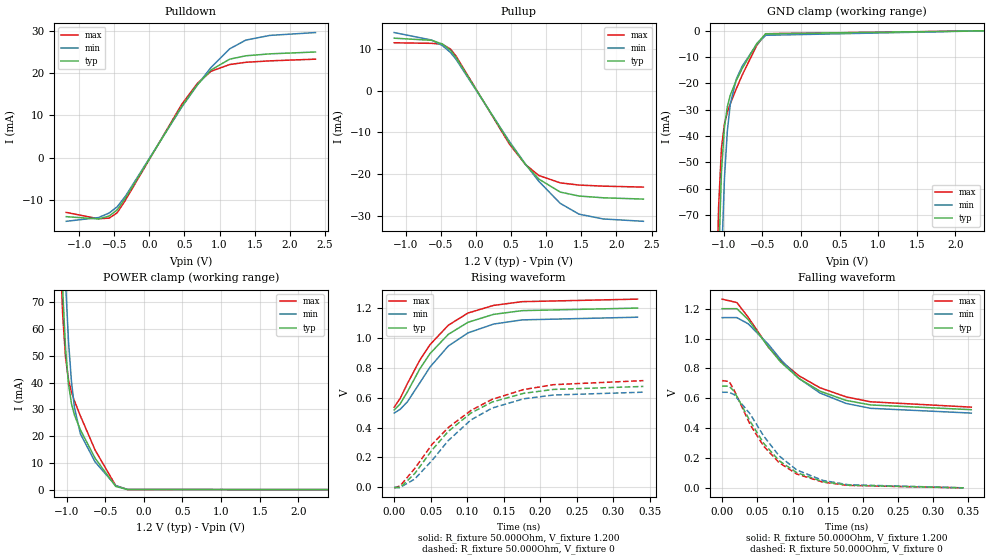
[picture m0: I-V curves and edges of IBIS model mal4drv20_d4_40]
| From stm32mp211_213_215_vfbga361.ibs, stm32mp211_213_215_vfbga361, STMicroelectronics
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[Model] mal4drv20_d4_40
Model_type   I/O
Polarity   Non-Inverting
Enable   Active-High
C_comp   1.838pF   1.835pF   1.848pF
C_comp_pullup   938.881fF   931.604fF   947.115fF
C_comp_pulldown 782.410fF   779.859fF   796.520fF
Vinh = 668.000mV
Vinl = 532.000mV
Vmeas = 600.000mV
Vref = 600.000mV
Rref = 50Ohms
Cref = 0pF
[Model Spec]
Vinh   668.000mV   638.000mV   698.000mV
Vinl   532.000mV   502.000mV   562.000mV
Vmeas   600.000mV   570.000mV   630.000mV
Vref   600.000mV   570.000mV   630.000mV
D_overshoot_ampl_h 0.24 NA   NA
D_overshoot_ampl_l 0.24 NA   NA
D_overshoot_area_l 300.000m NA   NA
D_overshoot_area_h 300.000m NA   NA
[Receiver Thresholds]
Vth = 600.000mV
Vth_min = 570.000mV
Vth_max = 630.000mV
Vinh_ac = 68.000mV
Vinh_dc = 68.000mV
Vinl_ac = -68.000mV
Vinl_dc = -68.000mV
Tslew_ac = 5.000ns
Threshold_sensitivity = 0.5
Reference_supply Pullup_ref
[Temperature Range]   25.000   125.000   -40.000
[Voltage Range]   1.200V   1.140V   1.260V
[GND Clamp Reference]   0.00V   0.00V   0.00V
[C Comp Corner]
| variable   typ   min   max
C_comp 1.848pF   1.838pF   1.835pF
C_comp_pullup 938.881fF   947.115fF   931.604fF
C_comp_pulldown 779.859fF   796.520fF   782.410fF
[Pulldown Reference]   0.00V   0.00V   0.00V
[POWER Clamp Reference]   1.200V   1.140V   1.260V
[Pullup Reference]   1.200V   1.140V   1.260V
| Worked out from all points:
|   slope of the pulldown table from 0 to 0.18 V, typ, clamps not added: 36.7 ohm
|   slope of the pullup table from 0 to 0.18 V, typ, clamps not added: 37 ohm
|   GND clamp passes 1 mA (typ) near -0.45 V on its own axis
|   POWER clamp passes 1 mA (typ) near -0.35 V on its own axis
|   rising waveform, R_fixture 50.000Ohm, V_fixture 1.200: 20-80 % time 65.2ps typ, 66.6ps min, 65.5ps max; typ from 0.518 V to 1.2 V
|   rising waveform, R_fixture 50.000Ohm, V_fixture 0: 20-80 % time 85.5ps typ, 82.2ps min, 96ps max; typ from -0.002 V to 0.675 V
|   falling waveform, R_fixture 50.000Ohm, V_fixture 1.200: 20-80 % time 86.6ps typ, 85.3ps min, 92ps max; typ from 1.2 V to 0.524 V
|   falling waveform, R_fixture 50.000Ohm, V_fixture 0: 20-80 % time 63.9ps typ, 65.6ps min, 63.3ps max; typ from 0.681 V to 0 V
[GND Clamp]
-1.184V   -365mA     -429.3mA   -336.5mA
-1.107V   -152.4mA   -215.7mA   -121.1mA
-1.069V   -88.87mA   -140.5mA   -67.62mA
-1.031V   -53.54mA   -88.39mA   -44.48mA
-992.7mV  -36.7mA    -56.18mA   -35.42mA
-954.6mV  -28.78mA   -37.93mA   -30.92mA
-916.4mV  -24.43mA   -27.89mA   -27.7mA
-840mV    -18.89mA   -18.42mA   -22.12mA
-763.6mV  -14.38mA   -13.51mA   -16.88mA
-572.7mV  -4.818mA   -5.067mA   -5.477mA
-458.2mV  -1.146mA   -1.695mA   -1.103mA
2.367V    25.44nA    625nA      8.401nA
[Power Clamp]
-1.167V   197.6mA    234.2mA    183.1mA
-1.091V   108mA      144mA      94.42mA
-1.053V   75.21mA    107.2mA    65.93mA
-1.015V   52.65mA    77.42mA    49.33mA
-976.4mV  39.37mA    55.31mA    41.02mA
-938.2mV  32.15mA    40.29mA    36.48mA
-900mV    27.91mA    30.75mA    33.22mA
-823.6mV  22.42mA    20.91mA    27.62mA
-632.7mV  11.76mA    10.36mA    14.83mA
-365.4mV  1.178mA    1.496mA    1.508mA
-212.7mV  14.35uA    76.22uA    9.056uA
2.384V    -16.74nA   -562.7nA   -5.86nA
[Pulldown]
-1.184V   -14mA      -15.1mA    -13mA
-725.5mV  -14.55mA   -14.22mA   -14.51mA
-572.7mV  -13.85mA   -13.14mA   -14.34mA
-458.2mV  -12.39mA   -11.66mA   -13.08mA
-343.6mV  -9.649mA   -9.219mA   -10.16mA
458.2mV   12.06mA    11.85mA    12.52mA
687.3mV   17.29mA    17.27mA    17.63mA
878.2mV   20.74mA    21.33mA    20.43mA
1.145V    23.3mA     25.75mA    22.03mA
1.375V    24.1mA     27.82mA    22.56mA
1.718V    24.56mA    28.93mA    22.9mA
2.367V    25mA       29.6mA     23.3mA
[Pullup]
-1.167V   12.5mA     13.84mA    11.4mA
-632.7mV  11.99mA    12.05mA    11.27mA
-480mV    11.11mA    10.73mA    11.03mA
-365.4mV  9.622mA    9.099mA    9.915mA
-289.1mV  7.956mA    7.545mA    8.303mA
474.6mV   -12.4mA    -12.14mA   -12.77mA
703.6mV   -17.64mA   -17.55mA   -17.65mA
894.5mV   -21.13mA   -21.67mA   -20.27mA
1.2V      -24.23mA   -26.93mA   -22.03mA
1.467V    -25.17mA   -29.5mA    -22.55mA
1.811V    -25.59mA   -30.64mA   -22.81mA
2.384V    -25.9mA    -31.2mA    -23.04mA
[Ramp]
R_load=50.000Ohm
dV/dt_r   407.010mV/77.500ps  384.238mV/76.000ps  432.030mV/82.500ps
dV/dt_f   407.010mV/76.500ps  384.239mV/77.000ps  432.030mV/79.500ps
[Rising waveform]
R_fixture=50.000Ohm
V_fixture=1.200
V_fixture_min=1.140
V_fixture_max=1.260
0s        518mV      497.4mV    537mV
8ps       557.4mV    521.6mV    593.8mV
18ps      638.7mV    572.2mV    693.8mV
35ps      792.5mV    699mV      851.1mV
49ps      895.4mV    804.9mV    955.1mV
74ps      1.024V     945.9mV    1.085V
101ps     1.105V     1.034V     1.167V
136ps     1.158V     1.093V     1.218V
175ps     1.183V     1.121V     1.243V
333ps     1.2V       1.139V     1.26V
[Rising waveform]
R_fixture=50.000Ohm
V_fixture=0
0s        -2.468mV   -405.1uV   -3.651mV
8ps       -2.468mV   -405.1uV   9.098mV
28ps      91.4mV     54.71mV    125.4mV
52ps      250.9mV    181.2mV    288.7mV
74ps      374.5mV    313.1mV    400.1mV
105ps     497.4mV    451.2mV    514.7mV
134ps     570.9mV    530.6mV    589mV
177ps     629.2mV    592.5mV    654.4mV
218ps     655.4mV    618mV      687.2mV
341ps     675.4mV    637mV      714.4mV
[Falling waveform]
R_fixture=50.000Ohm
V_fixture=1.200
V_fixture_min=1.140
V_fixture_max=1.260
0s        1.2V       1.14V      1.264V
21ps      1.2V       1.14V      1.241V
37ps      1.127V     1.099V     1.143V
66ps      942.3mV    959.7mV    941.3mV
83ps      843.7mV    861.1mV    851.8mV
109ps     733.1mV    733.7mV    751.3mV
139ps     647.9mV    635.6mV    670.6mV
176ps     586.1mV    565.9mV    609.9mV
211ps     555.5mV    532.9mV    576.5mV
354ps     523.8mV    501.1mV    540.9mV
[Falling waveform]
R_fixture=50.000Ohm
V_fixture=0
0s        681.1mV    640.4mV    718.6mV
10ps      681.1mV    640.4mV    712.7mV
17ps      646.9mV    624.7mV    654.7mV
40ps      444.8mV    494mV      422.2mV
59ps      299mV      347.4mV    279.8mV
81ps      182.1mV    214.6mV    169.1mV
106ps     102.5mV    120.2mV    93.04mV
143ps     42.08mV    50.32mV    38.92mV
179ps     18.24mV    21.49mV    16.69mV
343ps     427.2uV    610.2uV    392.4uV
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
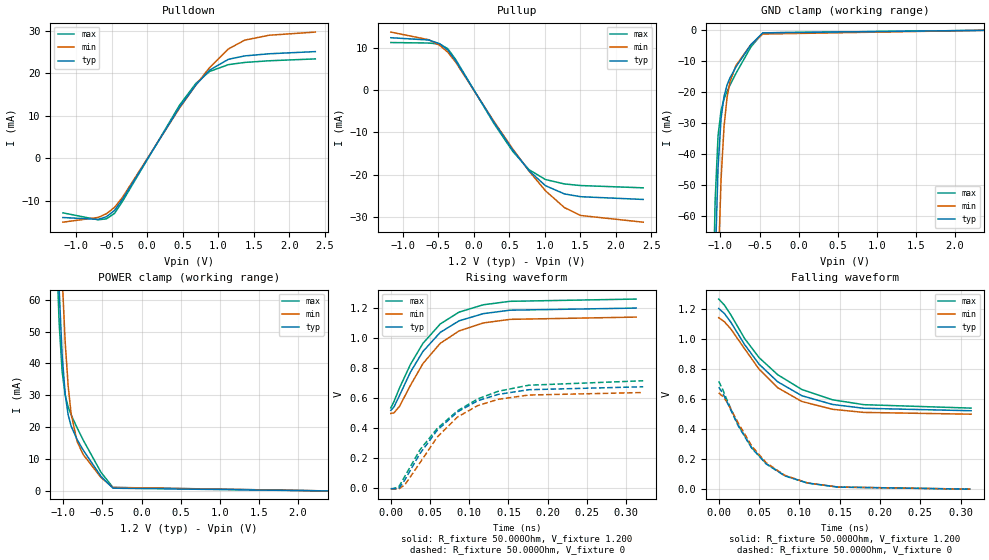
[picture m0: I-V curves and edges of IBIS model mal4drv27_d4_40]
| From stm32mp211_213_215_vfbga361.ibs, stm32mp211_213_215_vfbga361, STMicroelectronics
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[Model] mal4drv27_d4_40
Model_type   I/O
Polarity   Non-Inverting
Enable   Active-High
C_comp   1.656pF   1.652pF   1.661pF
C_comp_pullup   829.373fF   822.555fF   836.725fF
C_comp_pulldown 737.416fF   735.607fF   748.448fF
Vinh = 924.000mV
Vinl = 809.000mV
Vmeas = 867.000mV
Vref = 1.200V
Rref = 50Ohms
Cref = 0pF
[Model Spec]
Vinh   924.000mV   881.000mV   968.000mV
Vinl   809.000mV   766.000mV   853.000mV
Vmeas   867.000mV   823.000mV   910.000mV
Vref   1.200V   1.140V   1.260V
D_overshoot_ampl_h 0.24 NA   NA
D_overshoot_ampl_l 0.24 NA   NA
D_overshoot_area_l 300.000m NA   NA
D_overshoot_area_h 300.000m NA   NA
[Receiver Thresholds]
Vth = 867.000mV
Vth_min = 823.000mV
Vth_max = 910.000mV
Vinh_ac = 68.000mV
Vinh_dc = 68.000mV
Vinl_ac = -68.000mV
Vinl_dc = -68.000mV
Tslew_ac = 5.000ns
Threshold_sensitivity = 0.5
Reference_supply Pullup_ref
[Temperature Range]   25.000   125.000   -40.000
[Voltage Range]   1.200V   1.140V   1.260V
[GND Clamp Reference]   0.00V   0.00V   0.00V
[C Comp Corner]
| variable   typ   min   max
C_comp 1.661pF   1.656pF   1.652pF
C_comp_pullup 829.373fF   836.725fF   822.555fF
C_comp_pulldown 735.607fF   748.448fF   737.416fF
[Pulldown Reference]   0.00V   0.00V   0.00V
[POWER Clamp Reference]   1.200V   1.140V   1.260V
[Pullup Reference]   1.200V   1.140V   1.260V
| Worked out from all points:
|   slope of the pulldown table from 0 to 0.18 V, typ, clamps not added: 36.8 ohm
|   slope of the pullup table from 0 to 0.18 V, typ, clamps not added: 37.1 ohm
|   GND clamp passes 1 mA (typ) near -0.47 V on its own axis
|   POWER clamp passes 1 mA (typ) near -0.37 V on its own axis
|   rising waveform, R_fixture 50.000Ohm, V_fixture 1.200: 20-80 % time 55.4ps typ, 55.1ps min, 56ps max; typ from 0.52 V to 1.2 V
|   rising waveform, R_fixture 50.000Ohm, V_fixture 0: 20-80 % time 68ps typ, 63.2ps min, 78.3ps max; typ from -0.001 V to 0.676 V
|   falling waveform, R_fixture 50.000Ohm, V_fixture 1.200: 20-80 % time 68.9ps typ, 63.8ps min, 76.2ps max; typ from 1.2 V to 0.522 V
|   falling waveform, R_fixture 50.000Ohm, V_fixture 0: 20-80 % time 53.1ps typ, 52.9ps min, 53.3ps max; typ from 0.68 V to 0 V
[GND Clamp]
-1.184V   -313.6mA   -372.3mA   -285.9mA
-1.107V   -133mA     -190.9mA   -103.4mA
-1.069V   -76.66mA   -125mA     -55.43mA
-1.031V   -44.19mA   -77.99mA   -34.02mA
-992.7mV  -28.51mA   -48.19mA   -25.88mA
-954.6mV  -21.35mA   -31.1mA    -22.21mA
-916.4mV  -17.7mA    -21.78mA   -19.79mA
-878.2mV  -15.35mA   -16.61mA   -17.73mA
-801.8mV  -11.82mA   -11.34mA   -13.9mA
-610.9mV  -4.628mA   -4.618mA   -5.371mA
-458.2mV  -822.8uA   -1.198mA   -809uA
2.367V    18.95nA    454.6nA    6.243nA
[Power Clamp]
-1.167V   171.5mA    206.4mA    156.1mA
-1.091V   92.44mA    126.6mA    77.99mA
-1.053V   63.02mA    93.75mA    52.4mA
-1.015V   42.49mA    66.9mA     37.37mA
-976.4mV  30.34mA    46.72mA    30.02mA
-938.2mV  23.88mA    32.9mA     26.3mA
-900mV    20.31mA    24.15mA    23.84mA
-823.6mV  16.11mA    15.49mA    19.79mA
-747.3mV  12.87mA    11.46mA    16.02mA
-518.2mV  4.545mA    4.187mA    5.836mA
-365.4mV  856.5uA    1.078mA    1.107mA
2.384V    -12.74nA   -415.5nA   -4.625nA
[Pulldown]
-1.184V   -14mA      -15.1mA    -12.9mA
-687.3mV  -14.43mA   -13.98mA   -14.54mA
-572.7mV  -13.82mA   -13.11mA   -14.31mA
-458.2mV  -12.36mA   -11.62mA   -13.04mA
-343.6mV  -9.628mA   -9.199mA   -10.14mA
458.2mV   12.04mA    11.83mA    12.5mA
687.3mV   17.26mA    17.24mA    17.61mA
878.2mV   20.72mA    21.3mA     20.41mA
1.145V    23.29mA    25.73mA    22.03mA
1.375V    24.09mA    27.81mA    22.55mA
1.718V    24.59mA    28.96mA    22.94mA
2.367V    25.1mA     29.7mA     23.38mA
[Pullup]
-1.167V   12.5mA     13.84mA    11.36mA
-632.7mV  11.96mA    12.02mA    11.24mA
-480mV    11.09mA    10.7mA     11mA
-365.4mV  9.604mA    9.074mA    9.89mA
-250.9mV  6.931mA    6.616mA    7.242mA
283.6mV   -7.569mA   -7.358mA   -7.855mA
550.9mV   -14.2mA    -13.96mA   -14.54mA
780mV     -19.13mA   -19.21mA   -18.86mA
1.009V    -22.63mA   -23.84mA   -21.17mA
1.276V    -24.59mA   -27.84mA   -22.22mA
1.505V    -25.25mA   -29.71mA   -22.6mA
2.384V    -25.9mA    -31.3mA    -23.14mA
[Ramp]
R_load=50.000Ohm
dV/dt_r   406.620mV/62.500ps  383.909mV/60.000ps  431.640mV/68.000ps
dV/dt_f   406.620mV/62.000ps  383.909mV/59.500ps  431.640mV/66.500ps
[Rising waveform]
R_fixture=50.000Ohm
V_fixture=1.200
V_fixture_min=1.140
V_fixture_max=1.260
0s        519.8mV    498.9mV    535.7mV
4ps       541.8mV    503mV      577.8mV
11ps      617.1mV    545.4mV    667.7mV
25ps      773.8mV    685.4mV    824.7mV
41ps      911.6mV    830.9mV    965.5mV
63ps      1.038V     965.1mV    1.094V
87ps      1.115V     1.048V     1.173V
118ps     1.163V     1.101V     1.222V
152ps     1.186V     1.125V     1.245V
313ps     1.2V       1.14V      1.26V
[Rising waveform]
R_fixture=50.000Ohm
V_fixture=0
0s        -1.465mV   -3.842mV   -4.831mV
10ps      -1.465mV   -3.842mV   9.596mV
18ps      57.75mV    24.77mV    81.66mV
37ps      230.4mV    169.1mV    255.6mV
59ps      385.9mV    340.1mV    397.9mV
85ps      509.1mV    475.1mV    516.3mV
111ps     583.7mV    551.3mV    595.9mV
137ps     625.9mV    593.1mV    646.4mV
176ps     656.8mV    621.5mV    686.8mV
322ps     676.5mV    638.1mV    716.4mV
[Falling waveform]
R_fixture=50.000Ohm
V_fixture=1.200
V_fixture_min=1.140
V_fixture_max=1.260
0s        1.203V     1.142V     1.266V
7ps       1.17V      1.115V     1.226V
15ps      1.112V     1.067V     1.161V
32ps      963.7mV    935.7mV    1.004V
50ps      832.5mV    799.4mV    876.5mV
73ps      715.6mV    676mV      762.7mV
103ps     622.5mV    584.2mV    663.9mV
141ps     564.3mV    532.1mV    595.3mV
180ps     538.7mV    511.2mV    562.7mV
313ps     522.4mV    499.3mV    539.8mV
[Falling waveform]
R_fixture=50.000Ohm
V_fixture=0
0s        679.5mV    641.4mV    718.5mV
5ps       639.5mV    617.5mV    663.1mV
10ps      584.4mV    582.5mV    597.1mV
24ps      423.1mV    442.7mV    429.1mV
41ps      272.3mV    287mV      275.9mV
59ps      167.3mV    175.2mV    169.7mV
82ps      88.41mV    92.3mV     89.81mV
110ps     40.7mV     41.69mV    41.1mV
148ps     13.69mV    14.15mV    14.33mV
312ps     109.5uV    137.7uV    112.1uV
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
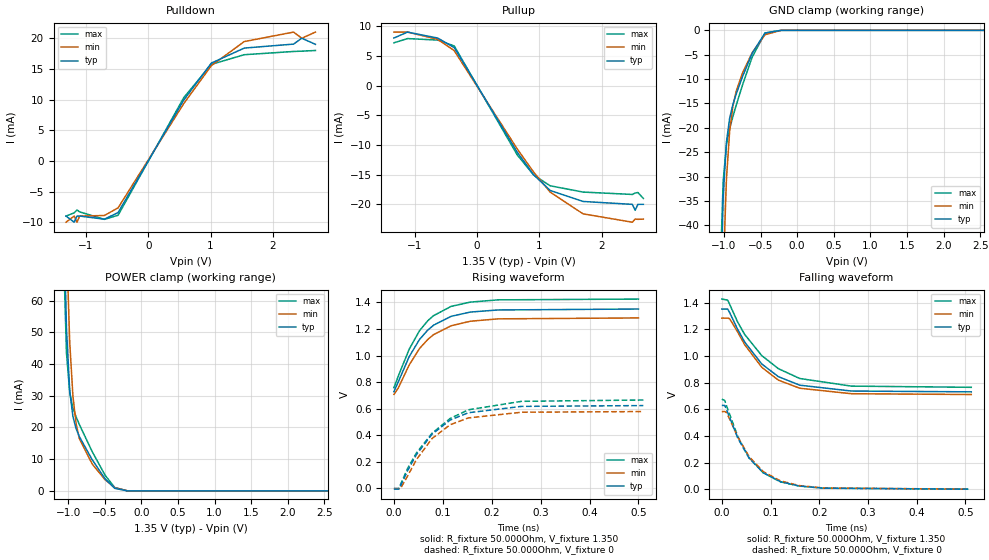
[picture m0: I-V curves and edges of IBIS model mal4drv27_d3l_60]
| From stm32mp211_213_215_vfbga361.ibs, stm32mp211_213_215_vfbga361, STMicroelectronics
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[Model] mal4drv27_d3l_60
Model_type   I/O
Polarity   Non-Inverting
Enable   Active-High
C_comp   1.684pF   1.663pF   1.711pF
C_comp_pullup   812.334fF   800.254fF   826.800fF
C_comp_pulldown   769.309fF   756.297fF   787.425fF
Vinh = 805.000mV
Vinl = 545.000mV
Vmeas = 675.000mV
Vref = 675.000mV
Rref = 50Ohms
Cref = 0pF
[Model Spec]
Vinh   805.000mV   772.000mV   855.000mV
Vinl   545.000mV   512.000mV   595.000mV
Vmeas   675.000mV   642.000mV   725.000mV
Vref   675.000mV   642.000mV   725.000mV
D_overshoot_ampl_h 0.4 NA   NA
D_overshoot_ampl_l 0.4 NA   NA
D_overshoot_area_l 110.000m NA   NA
D_overshoot_area_h 110.000m NA   NA
[Temperature Range]   25.000   125.000   -40.000
[Voltage Range]   1.350V   1.283V   1.425V
[GND Clamp Reference]   0.00V   0.00V   0.00V
[C Comp Corner]
| variable   typ   min   max
C_comp   1.684pF   1.663pF   1.711pF
C_comp_pullup   812.334fF   800.254fF   826.800fF
C_comp_pulldown   769.309fF   756.297fF   787.425fF
[Pulldown Reference]   0.00V   0.00V   0.00V
[POWER Clamp Reference]   1.350V   1.283V   1.425V
[Pullup Reference]   1.350V   1.283V   1.425V
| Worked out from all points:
|   slope of the pulldown table from 0 to 0.203 V, typ, clamps not added: 55.4 ohm
|   slope of the pullup table from 0 to 0.203 V, typ, clamps not added: 55.2 ohm
|   GND clamp passes 1 mA (typ) near -0.47 V on its own axis
|   POWER clamp passes 1 mA (typ) near -0.37 V on its own axis
|   rising waveform, R_fixture 50.000Ohm, V_fixture 1.350: 20-80 % time 65.7ps typ, 68.1ps min, 64.5ps max; typ from 0.728 V to 1.35 V
|   rising waveform, R_fixture 50.000Ohm, V_fixture 0: 20-80 % time 81.2ps typ, 76.1ps min, 92.3ps max; typ from -0.006 V to 0.623 V
|   falling waveform, R_fixture 50.000Ohm, V_fixture 1.350: 20-80 % time 82.6ps typ, 79.1ps min, 92.4ps max; typ from 1.35 V to 0.73 V
|   falling waveform, R_fixture 50.000Ohm, V_fixture 0: 20-80 % time 64.5ps typ, 67.3ps min, 63.4ps max; typ from 0.628 V to 0 V
[GND Clamp]
-1.318V   -672mA     -638mA     -661.1mA
-1.054V   -60.41mA   -84.99mA   -50.75mA
-1.011V   -34.02mA   -49.92mA   -30.84mA
-966.7mV  -22.91mA   -30.54mA   -23.58mA
-922.7mV  -18.04mA   -20.68mA   -20.16mA
-878.8mV  -15.25mA   -15.56mA   -17.69mA
-834.8mV  -13.14mA   -12.55mA   -15.44mA
-747mV    -9.486mA   -8.743mA   -11.21mA
-615.2mV  -4.709mA   -4.591mA   -5.504mA
-439.4mV  -562.2uA   -889.5uA   -546.1uA
-219.7mV  -954.1nA   -9.356uA   -215nA
2.68V     18.98nA    945nA      23.53nA
[Power Clamp]
-1.33V    889mA      842.2mA    872.8mA
-1.067V   94.44mA    130.9mA    77.96mA
-1.023V   51.04mA    78.45mA    43.53mA
-978.8mV  31.54mA    46.94mA    31.01mA
-934.8mV  23.45mA    29.85mA    26.15mA
-890.9mV  19.58mA    21.13mA    23.3mA
-847mV    17.11mA    16.47mA    20.93mA
-671.2mV  9.815mA    8.474mA    12.37mA
-495.5mV  3.823mA    3.529mA    4.955mA
-363.6mV  819.5uA    1.024mA    1.072mA
-187.9mV  4.227uA    28.6uA     2.566uA
2.668V    -29.12nA   -796.8nA   -15.73nA
[Pulldown]
-1.318V   -9mA       -10mA      -9mA
-1.186V   -10mA      -9mA       -8.475mA
-1.142V   -9mA       -10mA      -8mA
-1.099V   -9mA       -9mA       -8.319mA
-703mV    -9.511mA   -8.91mA    -9.54mA
-483.3mV  -8.432mA   -7.665mA   -8.87mA
571.2mV   9.942mA    9.369mA    10.34mA
1.011V    15.94mA    15.52mA    15.73mA
1.538V    18.39mA    19.45mA    17.31mA
2.329V    19.04mA    21mA       17.84mA
2.461V    20mA       20mA       17.89mA
2.68V     19mA       21mA       18mA
[Pullup]
-1.33V    8mA        9mA        7.193mA
-1.111V   9mA        9mA        7.908mA
-627.3mV  7.993mA    7.774mA    7.654mA
-363.6mV  6.396mA    5.879mA    6.67mA
647mV     -11.23mA   -10.68mA   -11.68mA
910.6mV   -15.03mA   -14.58mA   -15.07mA
1.174V    -17.66mA   -17.93mA   -16.87mA
1.702V    -19.51mA   -21.6mA    -17.93mA
2.492V    -20mA      -23mA      -18.33mA
2.536V    -21mA      -22.47mA   -18.09mA
2.58V     -20mA      -22.52mA   -18mA
2.668V    -20mA      -22.48mA   -19mA
[Ramp]
R_load=50.000Ohm
dV/dt_r   372.900mV/74.500ps  345.298mV/73.000ps  397.800mV/79.500ps
dV/dt_f   372.900mV/75.000ps  345.299mV/74.500ps  397.800mV/78.500ps
[Rising waveform]
R_fixture=50.000Ohm
V_fixture=1.350
V_fixture_min=1.283
V_fixture_max=1.425
0s        728mV      707mV      758mV
9ps       802mV      756mV      845mV
31ps      990mV      927mV      1.046V
52ps      1.119V     1.051V     1.185V
69ps      1.191V     1.12V      1.261V
81ps      1.228V     1.157V     1.3V
117ps     1.295V     1.224V     1.37V
156ps     1.327V     1.258V     1.402V
213ps     1.343V     1.276V     1.419V
500ps     1.35V      1.283V     1.425V
[Rising waveform]
R_fixture=50.000Ohm
V_fixture=0
0s        -6.304mV   -2.587mV   -973.7uV
10ps      -6.304mV   -2.587mV   -973.7uV
14ps      21.86mV    1.806mV    33.3mV
28ps      133mV      92.81mV    150mV
46ps      254mV      216mV      266mV
78ps      408mV      375mV      415mV
115ps     514mV      479mV      526mV
152ps     569mV      530mV      591mV
261ps     617mV      573mV      655mV
510ps     623mV      578mV      665mV
[Falling waveform]
R_fixture=50.000Ohm
V_fixture=1.350
V_fixture_min=1.283
V_fixture_max=1.425
0s        1.351V     1.283V     1.426V
12ps      1.351V     1.283V     1.418V
16ps      1.325V     1.279V     1.387V
32ps      1.202V     1.182V     1.257V
47ps      1.103V     1.083V     1.16V
82ps      939mV      914mV      1.002V
116ps     844mV      818mV      904mV
160ps     780mV      757mV      830mV
266ps     736mV      716mV      773mV
512ps     730mV      710mV      764mV
[Falling waveform]
R_fixture=50.000Ohm
V_fixture=0
0s        628mV      582mV      675mV
6ps       628mV      582mV      665mV
10ps      593mV      573mV      622mV
33ps      381mV      389mV      393mV
56ps      232mV      244mV      237mV
85ps      123mV      132mV      123mV
120ps     56.44mV    62.59mV    55.25mV
159ps     23.51mV    26.9mV     22.77mV
209ps     7.488mV    9.093mV    7.225mV
506ps     6.607uV    14.31uV    1.806uV
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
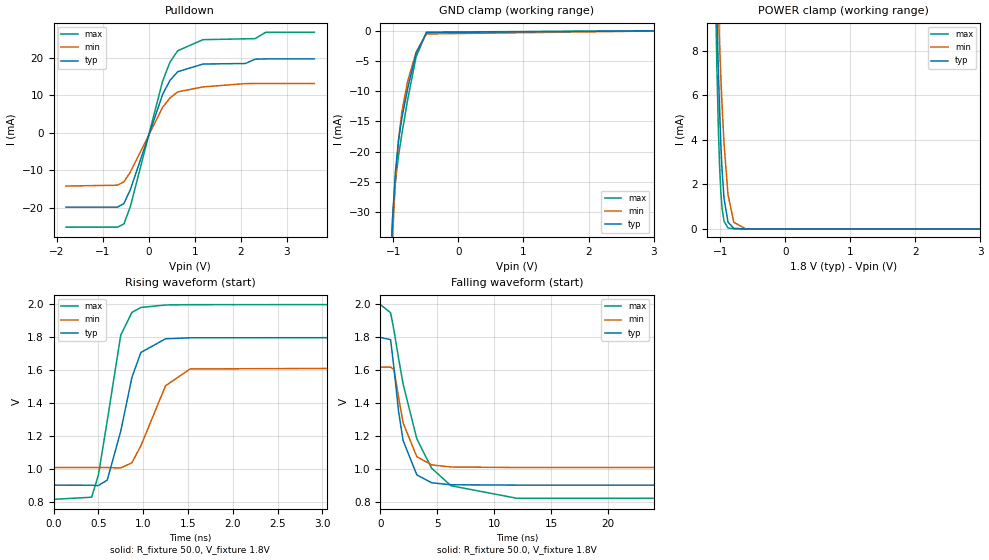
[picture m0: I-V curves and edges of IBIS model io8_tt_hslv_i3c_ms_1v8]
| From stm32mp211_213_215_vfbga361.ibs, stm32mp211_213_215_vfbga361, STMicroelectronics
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[Model]   io8_tt_hslv_i3c_ms_1v8
Model_type I/O_open_drain
Polarity   Non-Inverting
Enable   Active-Low
| CAP_THRESHOLD on pad IOTT is "UDTCAPC" :
| Rising=30.0% of vddiov33m   Falling=70.0% of vddiov33m
| C_comp min and max val. don't necessarily correlate with the min and max pvt
| but are the smallest and greatest pad capacitance found.
| var   typ   min   max
C_comp   1.23120pF  1.11692pF  1.38090pF
|C_comp_pulldown   1.23120pF  1.11692pF  1.38090pF
Vinl = 810.0mV
Vinh = 1.0V
Vmeas = 900.0mV   | Reference voltage for timing measurements
Cref  = 50.0pF   | Timing specification test load capacitance value
Rref  = 1.0MOhm   | Timing specification test load resistance value
Vref  = 990.0mV   | Timing specification test load voltage
[Model Spec]
| TIME_THRESHOLD on pin ZIV08M is "CMOS" :
| Rising=50.0% of vddv08m   Falling=50.0% of vddv08m
Vinl 675.70000mV 623.70000mV 735.70000mV
Vinh 1.12730V 1.01130V 1.24930V
| variable   typ   min   max
[Temperature Range] 25.0 125.0 -40.0
| variable   typ   min   max
[Voltage Range] 1.8V 1.62V 2.0V
| variable   typ   min   max
[POWER Clamp Reference] 1.8V 1.62V 2.0V
| variable   typ   min   max
[GND Clamp Reference] 0V 0V 0V
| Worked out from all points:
|   slope of the pulldown table from 0 to 0.27 V, typ, clamps not added: 28.9 ohm
|   GND clamp passes 1 mA (typ) near -0.55 V on its own axis
|   POWER clamp passes 1 mA (typ) near -0.93 V on its own axis
|   rising waveform, R_fixture 50.0, V_fixture 1.8V: 20-80 % time 220ps typ, 275ps min, 197ps max; typ from 0.904 V to 1.8 V
|   falling waveform, R_fixture 50.0, V_fixture 1.8V: 20-80 % time 1.14ns typ, 1.22ns min, 2.67ns max; typ from 1.8 V to 0.904 V
[POWER Clamp]
-1.8V     152.1mA    105.6mA    221.1mA
-1.07V    12.07mA    13.61mA    10.38mA
-1.05V    9.569mA    11.75mA    7.248mA
-1.03V    7.339mA    9.993mA    4.743mA
-1.01V    5.42mA     8.357mA    2.898mA
-990mV    3.841mA    6.859mA    1.662mA
-970mV    2.609mA    5.513mA    906.4uA
-940mV    1.358mA    3.806mA    344.1uA
-880mV    308.2uA    1.548mA    45.5uA
-790mV    28.46uA    298.8uA    2.106uA
-610mV    211.8nA    7.522uA    9.52nA
3.6V      0A         0A         0A
[GND Clamp]
-1.8V     -1.222A    -1.193A    -1.238A
-1.05V    -42.33mA   -45.55mA   -41.2mA
-1.04V    -38.89mA   -42.1mA    -37.88mA
-1.03V    -35.83mA   -38.98mA   -35.06mA
-1.01V    -30.7mA    -33.54mA   -30.61mA
-970mV    -23.47mA   -25.17mA   -24.97mA
-920mV    -18.06mA   -18.06mA   -20.63mA
-870mV    -14.51mA   -13.44mA   -17.13mA
-780mV    -9.532mA   -8.354mA   -11.38mA
-650mV    -3.743mA   -3.581mA   -4.327mA
-490mV    -324.1uA   -556uA     -259.6uA
3.6V      66.06nA    2.767uA    18.5nA
| variable   typ   min   max
[Pullup Reference] 1.8V 1.62V 2.0V
| variable   typ   min   max
[Pulldown Reference] 0V 0V 0V
[Pulldown]
-1.8V     -19.85mA   -14.22mA   -25.2mA
-680mV    -19.85mA   -13.99mA   -25.2mA
-540mV    -18.89mA   -13.07mA   -24.34mA
-400mV    -15.16mA   -10.48mA   -19.7mA
300mV     10.22mA    6.776mA    13.77mA
460mV     14.01mA    9.309mA    18.88mA
630mV     16.33mA    10.94mA    21.94mA
1.18V     18.38mA    12.27mA    24.89mA
2.1V      18.52mA    13.15mA    25.11mA
2.31V     19.67mA    13.17mA    25.16mA
2.54V     19.76mA    13.17mA    26.85mA
3.6V      19.76mA    13.17mA    26.85mA
[Ramp]
dV/dt_r 537.55524mV/218.98043ps 365.30936mV/274.0488ps 709.20405mV/196.296ps
dV/dt_f 537.59486mV/1.13706ns 365.35596mV/1.21952ns 709.23758mV/2.6706ns
R_load = 50.0
| Removed startup time: 0s 0s 0s  .
| Removed end time: 6.975ns.
[Rising Waveform]
R_fixture   = 50.0
V_fixture   = 1.8V
V_fixture_min = 1.62V
V_fixture_max = 2.0V
0s        904mV      1.011V     817.9mV
425ps     903.7mV    1.011V     830.7mV
500ps     901.1mV    1.011V     964mV
600ps     935.1mV    1.011V     1.296V
750ps     1.231V     1.008V     1.814V
875ps     1.558V     1.04V      1.952V
975ps     1.709V     1.143V     1.982V
1.25ns    1.792V     1.507V     1.997V
1.525ns   1.798V     1.609V     1.999V
6.975ns   1.8V       1.62V      2V
| Removed startup time: 0s 0s 0s  .
| Removed end time: 399.9ns.
[Falling Waveform]
R_fixture   = 50.0
V_fixture   = 1.8V
V_fixture_min = 1.62V
V_fixture_max = 2.0V
0s        1.8V       1.62V      2V
900ps     1.787V     1.62V      1.95V
1.2ns     1.612V     1.605V     1.842V
1.6ns     1.352V     1.437V     1.674V
2ns       1.174V     1.281V     1.517V
3.2ns     966.5mV    1.077V     1.186V
4.5ns     918.4mV    1.027V     1.007V
6.2ns     906.3mV    1.014V     900.4mV
12ns      904mV      1.011V     824.2mV
399.9ns   904mV      1.011V     817.9mV
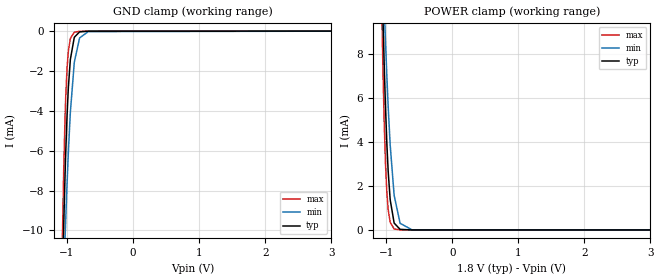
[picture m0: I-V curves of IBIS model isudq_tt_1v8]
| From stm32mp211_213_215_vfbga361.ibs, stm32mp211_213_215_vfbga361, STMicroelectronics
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[Model]   isudq_tt_1v8
Model_type Input
Polarity   Non-Inverting
Enable   Active-Low
| CAP_THRESHOLD on pad IOTT is "UDTCAPC" :
| Rising=30.0% of vddiov33m   Falling=70.0% of vddiov33m
| C_comp min and max val. don't necessarily correlate with the min and max pvt
| but are the smallest and greatest pad capacitance found.
| var   typ   min   max
C_comp   938.89377fF  935.36557fF  1.13047pF
|C_comp_pullup   537.51500fF  531.51000fF  540.53500fF
|C_comp_pulldown   401.37877fF  403.85557fF  589.93516fF
Vinl = 810.0mV
Vinh = 1.0V
[Model Spec]
| TIME_THRESHOLD on pin ZIV08M is "CMOS" :
| Rising=50.0% of vddv08m   Falling=50.0% of vddv08m
Vinl 1.25470V 887.70000mV 1.27470V
Vinh 1.28430V 1.14430V 1.42630V
| variable   typ   min   max
[Temperature Range] 25.0 125.0 -40.0
| variable   typ   min   max
[Voltage Range] 1.8V 1.62V 2.0V
| variable   typ   min   max
[POWER Clamp Reference] 1.8V 1.62V 2.0V
| variable   typ   min   max
[GND Clamp Reference] 0V 0V 0V
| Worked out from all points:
|   GND clamp passes 1 mA (typ) near -0.94 V on its own axis
|   POWER clamp passes 1 mA (typ) near -0.93 V on its own axis
[POWER Clamp]
-1.8V     154.4mA    107.2mA    224.4mA
-1.07V    12.25mA    13.82mA    10.53mA
-1.05V    9.71mA     11.92mA    7.356mA
-1.03V    7.448mA    10.14mA    4.814mA
-1.01V    5.5mA      8.482mA    2.941mA
-990mV    3.897mA    6.962mA    1.686mA
-970mV    2.647mA    5.596mA    919.8uA
-940mV    1.378mA    3.864mA    349.1uA
-880mV    312.8uA    1.572mA    46.17uA
-790mV    28.9uA     304.1uA    2.138uA
-610mV    229.1nA    8.347uA    9.867nA
3.6V      0A         0A         0A
[GND Clamp]
-1.8V     -183.8mA   -128.6mA   -265.6mA
-1.07V    -12.59mA   -14.73mA   -10.39mA
-1.05V    -9.719mA   -12.51mA   -6.951mA
-1.03V    -7.218mA   -10.44mA   -4.332mA
-1.02V    -6.123mA   -9.474mA   -3.329mA
-1V       -4.261mA   -7.674mA   -1.875mA
-980mV    -2.837mA   -6.076mA   -1.005mA
-950mV    -1.431mA   -4.085mA   -375.1uA
-890mV    -310.3uA   -1.565mA   -54.81uA
-810mV    -40.67uA   -344.5uA   -10.8uA
-680mV    -5.357uA   -27.75uA   -4.997uA
3.6V      13.15nA    276.9nA    16.51nA
